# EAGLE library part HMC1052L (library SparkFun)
HMC1052L Dual axis magnetic sensor. Used for compass and magnetometer applications. Schematic and footprint are not tested and probably need fixing. Spark Fun Electronics SKU : COM-00708

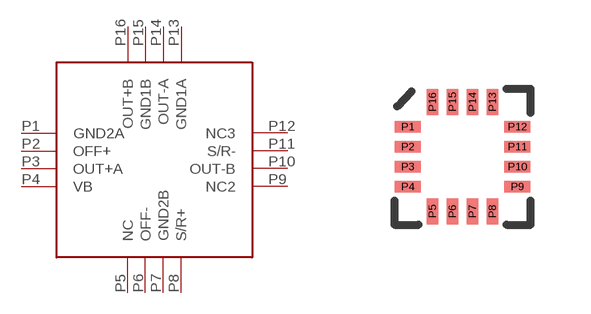
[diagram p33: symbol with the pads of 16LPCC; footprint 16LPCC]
Designator prefix -

## HMC1052L  [16LPCC]
P1  GND2A
P2  OFF+
P3  OUT+A
P4  VB
P5  NC
P6  OFF-
P7  GND2B
P8  S/R+
P9  NC2
P10  OUT-B
P11  S/R-
P12  NC3
P13  GND1A
P14  OUT-A
P15  GND1B
P16  OUT+B

## Footprint 16LPCC (pad centres in mm)
smd 0.65 x 0.28: P1 -1.37,0.75; P2 -1.37,0.25; P3 -1.37,-0.25; P4 -1.37,-0.75; P9 1.37,-0.75; P10 1.37,-0.25; P11 1.37,0.25; P12 1.37,0.75
smd 0.28 x 0.65: P5 -0.75,-1.37; P6 -0.25,-1.37; P7 0.25,-1.37; P8 0.75,-1.37; P13 0.75,1.37; P14 0.25,1.37; P15 -0.25,1.37; P16 -0.75,1.37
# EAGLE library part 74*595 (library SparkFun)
8-bit SHIFT REGISTER, output latch

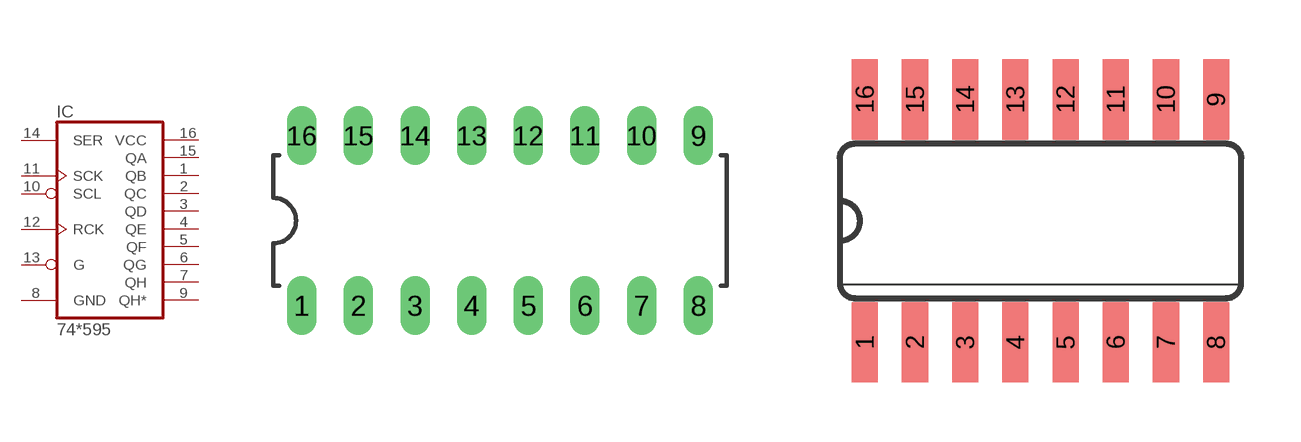
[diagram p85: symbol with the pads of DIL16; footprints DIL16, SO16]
Designator prefix IC

## 74LS595N  [DIL16]
1  QB  hiz
2  QC  hiz
3  QD  hiz
4  QE  hiz
5  QF  hiz
6  QG  hiz
7  QH  hiz
8  GND  pwr
9  QH*  hiz
10  SCL  in
11  SCK  in
12  RCK  in
13  G  in
14  SER  in
15  QA  hiz
16  VCC  pwr

## 74LS595D  [SO16]
Pads as for DIL16

## 74LS595FK  [LCC20]
2  QB  hiz
3  QC  hiz
4  QD  hiz
5  QE  hiz
7  QF  hiz
8  QG  hiz
9  QH  hiz
10  GND  pwr
12  QH*  hiz
13  SCL  in
14  SCK  in
15  RCK  in
17  G  in
18  SER  in
19  QA  hiz
20  VCC  pwr

## 74595  [TSSOP16]
Pads as for DIL16

## Footprint DIL16 (pad centres in mm)
Dual In Line Package
drill 0.813 long: 1 -8.89,-3.81; 2 -6.35,-3.81; 3 -3.81,-3.81; 4 -1.27,-3.81; 5 1.27,-3.81; 6 3.81,-3.81; 7 6.35,-3.81; 8 8.89,-3.81; 9 8.89,3.81; 10 6.35,3.81; 11 3.81,3.81; 12 1.27,3.81; 13 -1.27,3.81; 14 -3.81,3.81; 15 -6.35,3.81; 16 -8.89,3.81

## Footprint SO16 (pad centres in mm)
Small Outline package 150 mil
smd 0.66 x 2.032: 1 -4.445,-3.073; 2 -3.175,-3.073; 3 -1.905,-3.073; 4 -0.635,-3.073; 5 0.635,-3.073; 6 1.905,-3.073; 7 3.175,-3.073; 8 4.445,-3.073; 9 4.445,3.073; 10 3.175,3.073; 11 1.905,3.073; 12 0.635,3.073; 13 -0.635,3.073; 14 -1.905,3.073; 15 -3.175,3.073; 16 -4.445,3.073

## Footprint LCC20 (pad centres in mm)
Leadless Chip Carrier Ceramic Package
smd 0.8 x 3.4: 1 0,3.8
smd 0.8 x 2: 2 -1.27,4.5; 3 -2.54,4.5; 9 -2.54,-4.5; 10 -1.27,-4.5; 11 0,-4.5; 12 1.27,-4.5; 13 2.54,-4.5; 19 2.54,4.5; 20 1.27,4.5
smd 2 x 0.8: 4 -4.5,2.54; 5 -4.5,1.27; 6 -4.5,0; 7 -4.5,-1.27; 8 -4.5,-2.54; 14 4.5,-2.54; 15 4.5,-1.27; 16 4.5,0; 17 4.5,1.27; 18 4.5,2.54

## Footprint TSSOP16 (pad centres in mm)
TSOP16 thin small outline package
smd 0.4 x 1.6: 1 -2.225,-2.85; 2 -1.575,-2.85; 3 -0.925,-2.85; 4 -0.275,-2.85; 5 0.375,-2.85; 6 1.025,-2.85; 7 1.675,-2.85; 8 2.325,-2.85; 9 2.325,3.05; 10 1.675,3.05; 11 1.025,3.05; 12 0.375,3.05; 13 -0.275,3.05; 14 -0.925,3.05; 15 -1.575,3.05; 16 -2.225,3.05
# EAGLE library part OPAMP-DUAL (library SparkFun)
Operational Amplifier

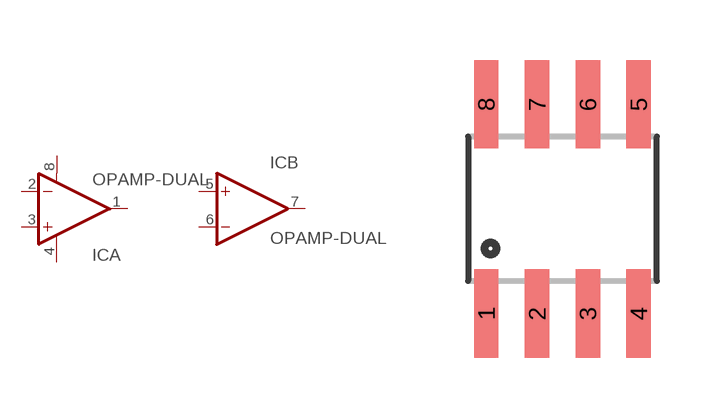
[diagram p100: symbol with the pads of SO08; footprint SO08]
Designator prefix IC; gates A=OP-AMP+- B=OP-AMP

## OPAMP-DUALU  [SO08]
1  A:OUT  out
2  A:-IN  in
3  A:+IN  in
4  A:V-  pwr
5  B:+IN  in
6  B:-IN  in
7  B:OUT  out
8  A:V+  pwr

## Footprint SO08 (pad centres in mm)
Small Outline Package Fits JEDEC packages (narrow SOIC-8)
smd 0.61 x 2.21: 1 -1.905,-2.616; 2 -0.635,-2.616; 3 0.635,-2.616; 4 1.905,-2.616; 5 1.905,2.616; 6 0.635,2.616; 7 -0.635,2.616; 8 -1.905,2.616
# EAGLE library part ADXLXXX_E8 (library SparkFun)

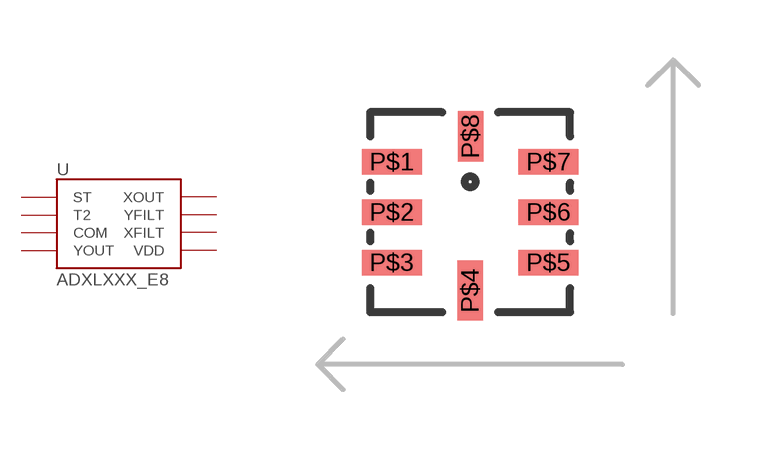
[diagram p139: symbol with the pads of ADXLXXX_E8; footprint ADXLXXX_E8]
Designator prefix -

## ADXLXXX_E8  [ADXLXXX_E8]
P$1  ST
P$2  T2
P$3  COM
P$4  YOUT
P$5  XOUT
P$6  YFILT
P$7  XFILT
P$8  VDD

## Footprint ADXLXXX_E8 (pad centres in mm)
smd 1.5 x 0.64: P$1 -1.96,1.26; P$2 -1.96,0; P$3 -1.96,-1.26; P$5 1.96,-1.26; P$6 1.96,0; P$7 1.96,1.26
smd 0.64 x 1.5: P$4 0,-1.96
smd 0.64 x 1.27: P$8 0.01,1.9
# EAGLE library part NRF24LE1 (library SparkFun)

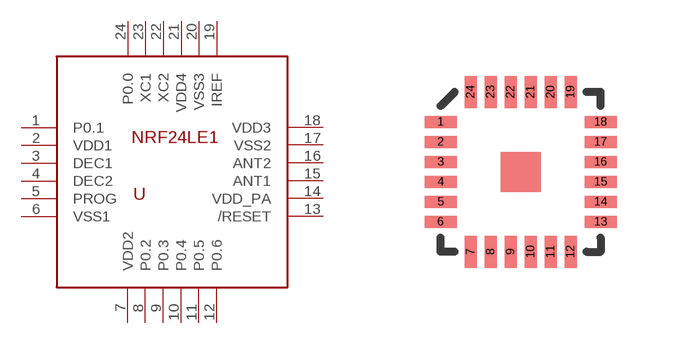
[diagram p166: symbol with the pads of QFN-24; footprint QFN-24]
Designator prefix -

## NRF24LE1  [QFN-24]
1  P0.1
2  VDD1
3  DEC1
4  DEC2
5  PROG
6  VSS1
7  VDD2
8  P0.2
9  P0.3
10  P0.4
11  P0.5
12  P0.6
13  /RESET
14  VDD_PA
15  ANT1
16  ANT2
17  VSS2
18  VDD3
19  IREF
20  VSS3
21  VDD4
22  XC2
23  XC1
24  P0.0

## Footprint QFN-24 (pad centres in mm)
smd 0.8 x 0.3: 1 -2,1.25; 2 -2,0.75; 3 -2,0.25; 4 -2,-0.25; 5 -2,-0.75; 6 -2,-1.25; 13 2,-1.25; 14 2,-0.75; 15 2,-0.25; 16 2,0.25; 17 2,0.75; 18 2,1.25
smd 0.3 x 0.8: 7 -1.25,-2; 8 -0.75,-2; 9 -0.25,-2; 10 0.25,-2; 11 0.75,-2; 12 1.25,-2; 19 1.25,2; 20 0.75,2; 21 0.25,2; 22 -0.25,2; 23 -0.75,2; 24 -1.25,2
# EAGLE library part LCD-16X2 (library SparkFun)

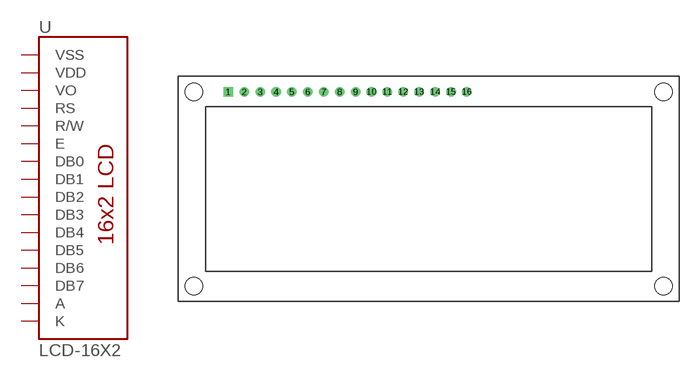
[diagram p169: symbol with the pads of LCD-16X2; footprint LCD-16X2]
Designator prefix -

## LCD-16X2  [LCD-16X2]
1  VSS  pwr
2  VDD  pwr
3  VO
4  RS  in
5  R/W  in
6  E  in
7  DB0
8  DB1
9  DB2
10  DB3
11  DB4
12  DB5
13  DB6
14  DB7
15  A  pwr
16  K  pwr

## Footprint LCD-16X2 (pad centres in mm)
drill 1.016 square: 1 -32,15.5
drill 1.016 round: 2 -29.46,15.5; 3 -26.92,15.5; 4 -24.38,15.5; 5 -21.84,15.5; 6 -19.3,15.5; 7 -16.76,15.5; 8 -14.22,15.5; 9 -11.68,15.5; 10 -9.14,15.5; 11 -6.6,15.5; 12 -4.06,15.5; 13 -1.52,15.5; 14 1.02,15.5; 15 3.56,15.5; 16 6.1,15.5
hole 2.8 at -37.5,15.5
hole 2.8 at -37.5,-15.5
hole 2.8 at 37.5,15.5
hole 2.8 at 37.5,-15.5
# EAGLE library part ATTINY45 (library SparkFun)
Atmel ATTiny45

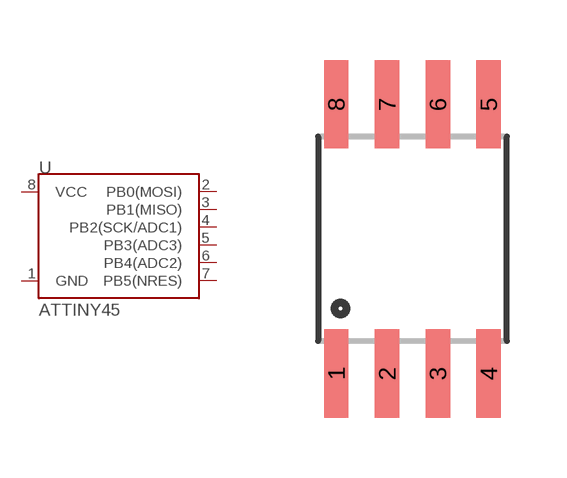
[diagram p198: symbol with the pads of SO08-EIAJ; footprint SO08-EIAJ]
Designator prefix -

## ATTINY45  [SO08-EIAJ]
1  GND
2  PB0(MOSI)
3  PB1(MISO)
4  PB2(SCK/ADC1)
5  PB3(ADC3)
6  PB4(ADC2)
7  PB5(NRES)
8  VCC

## Footprint SO08-EIAJ (pad centres in mm)
Fits EIAJ packages (wide version of the SOIC-8).
smd 0.61 x 2.21: 1 -1.905,-3.378; 2 -0.635,-3.378; 3 0.635,-3.378; 4 1.905,-3.378; 5 1.905,3.353; 6 0.635,3.353; 7 -0.635,3.353; 8 -1.905,3.353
